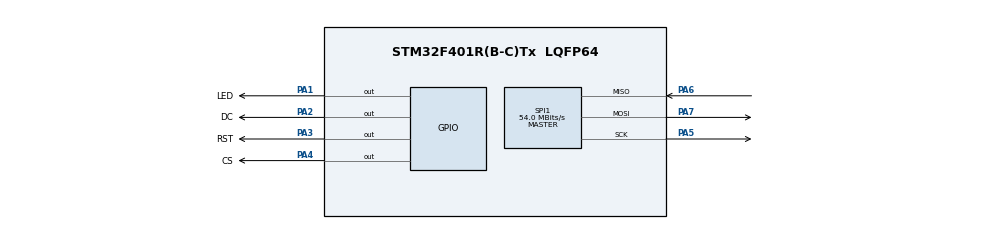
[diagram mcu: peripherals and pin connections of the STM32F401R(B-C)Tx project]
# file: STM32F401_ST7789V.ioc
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Dma.Request0=SPI1_RX
Dma.Request1=SPI1_TX
Dma.SPI1_RX.0.Direction=DMA_PERIPH_TO_MEMORY
Dma.SPI1_RX.0.FIFOMode=DMA_FIFOMODE_DISABLE
Dma.SPI1_RX.0.Instance=DMA2_Stream0
Dma.SPI1_RX.0.MemDataAlignment=DMA_MDATAALIGN_BYTE
Dma.SPI1_RX.0.MemInc=DMA_MINC_ENABLE
Dma.SPI1_RX.0.Mode=DMA_NORMAL
Dma.SPI1_RX.0.PeriphDataAlignment=DMA_PDATAALIGN_BYTE
Dma.SPI1_RX.0.PeriphInc=DMA_PINC_DISABLE
Dma.SPI1_RX.0.Priority=DMA_PRIORITY_VERY_HIGH
Dma.SPI1_TX.1.Direction=DMA_MEMORY_TO_PERIPH
Dma.SPI1_TX.1.FIFOMode=DMA_FIFOMODE_DISABLE
Dma.SPI1_TX.1.Instance=DMA2_Stream3
Dma.SPI1_TX.1.MemDataAlignment=DMA_MDATAALIGN_BYTE
Dma.SPI1_TX.1.MemInc=DMA_MINC_ENABLE
Dma.SPI1_TX.1.Mode=DMA_NORMAL
Dma.SPI1_TX.1.PeriphDataAlignment=DMA_PDATAALIGN_BYTE
Dma.SPI1_TX.1.PeriphInc=DMA_PINC_DISABLE
Dma.SPI1_TX.1.Priority=DMA_PRIORITY_VERY_HIGH
Mcu.Family=STM32F4
Mcu.Name=STM32F401R(B-C)Tx
Mcu.Package=LQFP64
NVIC.DMA2_Stream0_IRQn=true\:0\:0\:false\:false\:true\:false\:true\:true
NVIC.DMA2_Stream3_IRQn=true\:0\:0\:false\:false\:true\:false\:true\:true
NVIC.PriorityGroup=NVIC_PRIORITYGROUP_4
PA1.GPIO_Label=LED
PA1.Signal=GPIO_Output
PA2.GPIO_Label=DC
PA2.Signal=GPIO_Output
PA3.GPIO_Label=RST
PA3.Signal=GPIO_Output
PA4.GPIO_Label=CS
PA4.Signal=GPIO_Output
PA5.Mode=Full_Duplex_Master
PA5.Signal=SPI1_SCK
PA6.Mode=Full_Duplex_Master
PA6.Signal=SPI1_MISO
PA7.Mode=Full_Duplex_Master
PA7.Signal=SPI1_MOSI
PC14-OSC32_IN.Mode=LSE-External-Oscillator
PC14-OSC32_IN.Signal=RCC_OSC32_IN
PC15-OSC32_OUT.Mode=LSE-External-Oscillator
PC15-OSC32_OUT.Signal=RCC_OSC32_OUT
PH0\ -\ OSC_IN.Mode=HSE-External-Oscillator
PH0\ -\ OSC_IN.Signal=RCC_OSC_IN
PH1\ -\ OSC_OUT.Mode=HSE-External-Oscillator
PH1\ -\ OSC_OUT.Signal=RCC_OSC_OUT
ProjectManager.HeapSize=0x200
ProjectManager.StackSize=0x400
ProjectManager.TargetToolchain=STM32CubeIDE
RCC.48MHZClocksFreq_Value=108000000
RCC.AHBFreq_Value=108000000
RCC.APB1CLKDivider=RCC_HCLK_DIV4
RCC.APB1Freq_Value=27000000
RCC.APB1TimFreq_Value=54000000
RCC.APB2Freq_Value=108000000
RCC.APB2TimFreq_Value=108000000
RCC.CortexFreq_Value=108000000
RCC.HCLKFreq_Value=108000000
RCC.HSE_VALUE=25000000
RCC.HSI_VALUE=16000000
RCC.PLLM=25
RCC.PLLN=432
RCC.PLLP=RCC_PLLP_DIV4
RCC.PLLSourceVirtual=RCC_PLLSOURCE_HSE
RCC.SYSCLKFreq_VALUE=108000000
RCC.SYSCLKSource=RCC_SYSCLKSOURCE_PLLCLK
RCC.VCOOutputFreq_Value=432000000
SPI1.BaudRatePrescaler=SPI_BAUDRATEPRESCALER_2
SPI1.CLKPolarity=SPI_POLARITY_HIGH
SPI1.CalculateBaudRate=54.0 MBits/s
SPI1.DataSize=SPI_DATASIZE_8BIT
SPI1.Direction=SPI_DIRECTION_2LINES
SPI1.Mode=SPI_MODE_MASTER
SPI1.VirtualType=VM_MASTER
board=custom

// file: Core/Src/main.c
/* USER CODE BEGIN Header */
/**
  ******************************************************************************
  * @file           : main.c
  * @brief          : Main program body
  ******************************************************************************
  * @attention
  *
  * Copyright (c) 2024 STMicroelectronics.
  * All rights reserved.
  *
  * This software is licensed under terms that can be found in the LICENSE file
  * in the root directory of this software component.
  * If no LICENSE file comes with this software, it is provided AS-IS.
  *
  ******************************************************************************
  */
/* USER CODE END Header */
#include "main.h"
#include "dma.h"
#include "spi.h"
#include "gpio.h"

/* USER CODE BEGIN Includes */
#include "ST7789/st7789.h"
/* USER CODE END Includes */

/* USER CODE BEGIN PTD */

typedef struct {
    uint16_t width;            //LCD 宽度
    uint16_t height;            //LCD 高度
    uint16_t id;                //LCD ID
    uint8_t dir;            //横屏还是竖屏控制：0，竖屏；1，横屏。
    uint16_t wramcmd;        //开始写gram指令
    uint16_t setxcmd;        //设置x坐标指令
    uint16_t setycmd;        //设置y坐标指令
} _lcd_dev;

_lcd_dev lcddev;

/* USER CODE END PTD */

void SystemClock_Config(void);

int main(void)
{

  /* MCU Configuration--------------------------------------------------------*/

  /* Reset of all peripherals, Initializes the Flash interface and the Systick. */
  HAL_Init();

  /* Configure the system clock */
  SystemClock_Config();

  /* Initialize all configured peripherals */
  MX_GPIO_Init();
  MX_DMA_Init();
  MX_SPI1_Init();
  /* USER CODE BEGIN 2 */

    HAL_GPIO_WritePin(LED_GPIO_Port, LED_Pin, GPIO_PIN_SET);

    ST7789_Init();

    ST7789_Test();

  /* USER CODE END 2 */

  /* Infinite loop */
    while (1) {

    }
}

void SystemClock_Config(void)
{
  RCC_OscInitTypeDef RCC_OscInitStruct = {0};
  RCC_ClkInitTypeDef RCC_ClkInitStruct = {0};

  /** Configure the main internal regulator output voltage
  */
  __HAL_RCC_PWR_CLK_ENABLE();
  __HAL_PWR_VOLTAGESCALING_CONFIG(PWR_REGULATOR_VOLTAGE_SCALE2);

  /** Initializes the RCC Oscillators according to the specified parameters
  * in the RCC_OscInitTypeDef structure.
  */
  RCC_OscInitStruct.OscillatorType = RCC_OSCILLATORTYPE_HSE;
  RCC_OscInitStruct.HSEState = RCC_HSE_ON;
  RCC_OscInitStruct.PLL.PLLState = RCC_PLL_ON;
  RCC_OscInitStruct.PLL.PLLSource = RCC_PLLSOURCE_HSE;
  RCC_OscInitStruct.PLL.PLLM = 25;
  RCC_OscInitStruct.PLL.PLLN = 500;
  RCC_OscInitStruct.PLL.PLLP = RCC_PLLP_DIV4;
  RCC_OscInitStruct.PLL.PLLQ = 4;
  if (HAL_RCC_OscConfig(&RCC_OscInitStruct) != HAL_OK)
  {
    Error_Handler();
  }

  /** Initializes the CPU, AHB and APB buses clocks
  */
  RCC_ClkInitStruct.ClockType = RCC_CLOCKTYPE_HCLK|RCC_CLOCKTYPE_SYSCLK
                              |RCC_CLOCKTYPE_PCLK1|RCC_CLOCKTYPE_PCLK2;
  RCC_ClkInitStruct.SYSCLKSource = RCC_SYSCLKSOURCE_PLLCLK;
  RCC_ClkInitStruct.AHBCLKDivider = RCC_SYSCLK_DIV1;
  RCC_ClkInitStruct.APB1CLKDivider = RCC_HCLK_DIV4;
  RCC_ClkInitStruct.APB2CLKDivider = RCC_HCLK_DIV1;

  if (HAL_RCC_ClockConfig(&RCC_ClkInitStruct, FLASH_LATENCY_2) != HAL_OK)
  {
    Error_Handler();
  }
}

void Error_Handler(void)
{
    __disable_irq();
    while (1) {
    }
}
